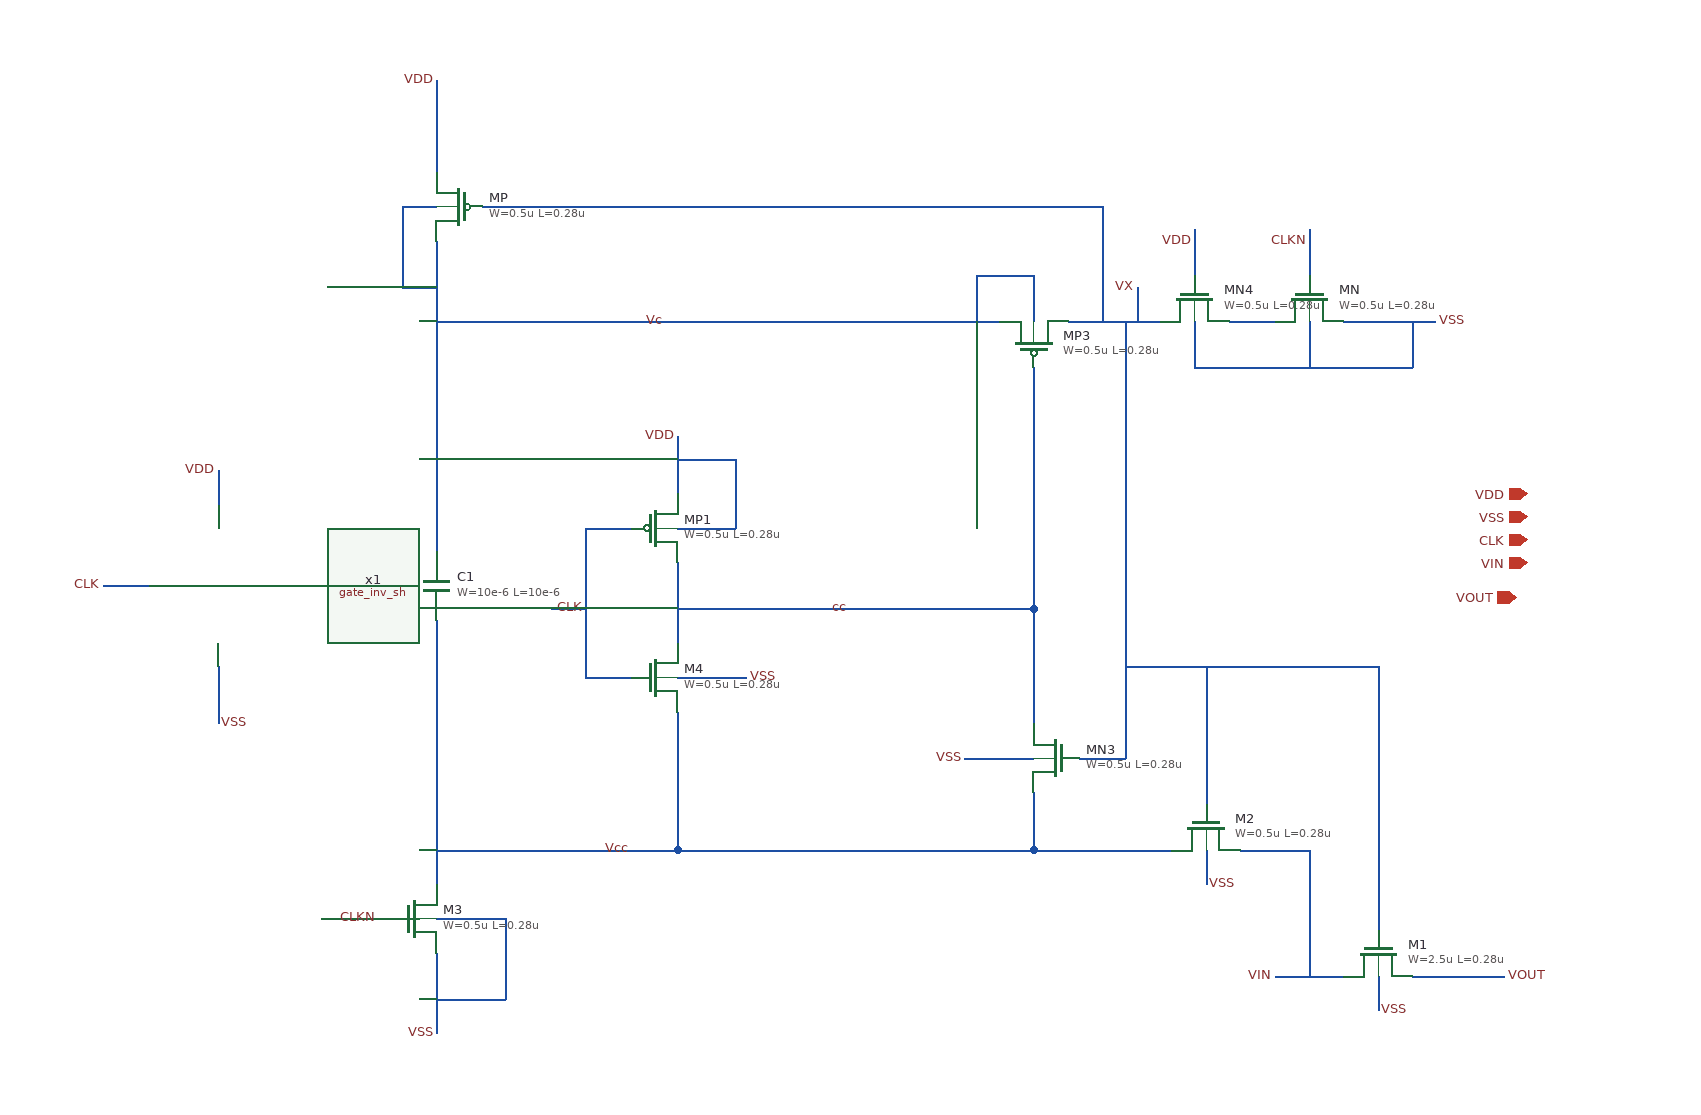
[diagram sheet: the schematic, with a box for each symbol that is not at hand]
v {xschem version=3.4.8RC file_version=1.3}
G {}
K {}
V {}
S {}
F {}
E {}
N 520 -490 520 -420 {lab=cc}
N 1000 -700 1040 -700 {lab=#net1}
N 1100 -700 1180 -700 {lab=VSS}
N 1070 -780 1070 -740 {lab=CLKN}
N 970 -780 970 -740 {lab=VDD}
N 860 -700 940 -700 {lab=VX}
N 1060 -130 1100 -130 {lab=VIN}
N 1130 -210 1130 -170 {lab=VX}
N 980 -320 980 -280 {lab=VX}
N 1130 -130 1130 -100 {lab=VSS}
N 980 -240 980 -210 {lab=VSS}
N 520 -450 830 -450 {lab=cc}
N 830 -360 830 -350 {lab=cc}
N 520 -360 520 -240 {lab=Vcc}
N 520 -240 830 -240 {lab=Vcc}
N 830 -290 830 -240 {lab=Vcc}
N 830 -450 830 -360 {lab=cc}
N 310 -150 310 -80 {lab=VSS}
N 310 -660 310 -500 {lab=Vc}
N 310 -440 310 -280 {lab=Vcc}
N 310 -280 310 -210 {lab=Vcc}
N 310 -770 310 -660 {lab=Vc}
N 310 -910 310 -830 {lab=VDD}
N 350 -800 890 -800 {lab=VX}
N 890 -800 890 -700 {lab=VX}
N 280 -800 310 -800 {lab=Vc}
N 280 -800 280 -730 {lab=Vc}
N 280 -730 310 -730 {lab=Vc}
N 310 -700 800 -700 {lab=Vc}
N 310 -180 370 -180 {lab=VSS}
N 370 -180 370 -110 {lab=VSS}
N 310 -110 370 -110 {lab=VSS}
N 210 -180 270 -180 {lab=CLKN}
N 440 -390 480 -390 {lab=CLK}
N 440 -520 480 -520 {lab=CLK}
N 440 -520 440 -390 {lab=CLK}
N 410 -450 440 -450 {lab=CLK}
N 470 -240 520 -240 {lab=Vcc}
N 310 -240 470 -240 {lab=Vcc}
N 520 -600 520 -550 {lab=VDD}
N 520 -390 580 -390 {lab=VSS}
N 520 -520 570 -520 {lab=VDD}
N 570 -580 570 -520 {lab=VDD}
N 520 -580 570 -580 {lab=VDD}
N 770 -320 830 -320 {lab=VSS}
N 830 -740 830 -700 {lab=Vc}
N 780 -740 830 -740 {lab=Vc}
N 780 -740 780 -700 {lab=Vc}
N 970 -700 970 -660 {lab=VSS}
N 970 -660 1160 -660 {lab=VSS}
N 1160 -700 1160 -660 {lab=VSS}
N 1070 -700 1070 -660 {lab=VSS}
N 910 -700 910 -320 {lab=VX}
N 910 -400 990 -400 {lab=VX}
N 990 -400 1090 -400 {lab=VX}
N 1160 -130 1240 -130 {lab=VOUT}
N 120 -400 120 -350 {lab=VSS}
N 120 -570 120 -540 {lab=VDD}
N 20 -470 60 -470 {lab=CLK}
N 200 -470 240 -470 {lab=CLKN}
N 890 -320 910 -320 {lab=VX}
N 870 -320 890 -320 {lab=VX}
N 830 -240 960 -240 {lab=Vcc}
N 1130 -400 1130 -210 {lab=VX}
N 1090 -400 1130 -400 {lab=VX}
N 1040 -130 1060 -130 {lab=VIN}
N 1010 -240 1070 -240 {lab=VIN}
N 1070 -240 1070 -130 {lab=VIN}
N 980 -400 980 -320 {lab=VX}
N 920 -730 920 -700 {lab=VX}
N 830 -470 830 -450 {lab=cc}
N 830 -660 830 -470 {lab=cc}
C {iopin.sym} 1260 -510 0 0 {name=p2 lab=CLK}
C {iopin.sym} 1260 -530 0 0 {name=p3 lab=VSS}
C {iopin.sym} 1260 -550 0 0 {name=p4 lab=VDD}
C {iopin.sym} 1250 -460 0 0 {name=p5 lab=VOUT}
C {iopin.sym} 1260 -490 0 0 {name=p6 lab=VIN}
C {lab_wire.sym} 310 -910 0 0 {name=p7 sig_type=std_logic lab=VDD}
C {lab_wire.sym} 970 -770 0 0 {name=p8 sig_type=std_logic lab=VDD}
C {lab_wire.sym} 1180 -700 0 1 {name=p10 sig_type=std_logic lab=VSS}
C {lab_wire.sym} 1240 -130 0 1 {name=p11 sig_type=std_logic lab=VOUT}
C {lab_wire.sym} 1040 -130 2 1 {name=p12 sig_type=std_logic lab=VIN}
C {lab_wire.sym} 980 -210 2 0 {name=p14 sig_type=std_logic lab=VSS}
C {lab_wire.sym} 770 -320 2 1 {name=p15 sig_type=std_logic lab=VSS}
C {lab_wire.sym} 310 -80 2 1 {name=p16 sig_type=std_logic lab=VSS}
C {lab_wire.sym} 580 -390 2 0 {name=p17 sig_type=std_logic lab=VSS}
C {lab_wire.sym} 520 -600 0 0 {name=p20 sig_type=std_logic lab=VDD}
C {lab_wire.sym} 120 -350 2 0 {name=p21 sig_type=std_logic lab=VSS}
C {lab_wire.sym} 20 -470 0 0 {name=p22 sig_type=std_logic lab=CLK}
C {lab_wire.sym} 120 -570 0 0 {name=p23 sig_type=std_logic lab=VDD}
C {lab_wire.sym} 1070 -770 0 0 {name=p26 sig_type=std_logic lab=CLKN
}
C {symbols/nfet_03v3.sym} 1070 -720 3 1 {name=MN
L=0.28u
W=0.5u
nf=1
m=2
ad="'int((nf+1)/2) * W/nf * 0.18u'"
pd="'2*int((nf+1)/2) * (W/nf + 0.18u)'"
as="'int((nf+2)/2) * W/nf * 0.18u'"
ps="'2*int((nf+2)/2) * (W/nf + 0.18u)'"
nrd="'0.18u / W'" nrs="'0.18u / W'"
sa=0 sb=0 sd=0
model=nfet_03v3
spiceprefix=X
}
C {symbols/nfet_03v3.sym} 850 -320 0 1 {name=MN3
L=0.28u
W=0.5u
nf=1
m=1
ad="'int((nf+1)/2) * W/nf * 0.18u'"
pd="'2*int((nf+1)/2) * (W/nf + 0.18u)'"
as="'int((nf+2)/2) * W/nf * 0.18u'"
ps="'2*int((nf+2)/2) * (W/nf + 0.18u)'"
nrd="'0.18u / W'" nrs="'0.18u / W'"
sa=0 sb=0 sd=0
model=nfet_03v3
spiceprefix=X
}
C {symbols/pfet_03v3.sym} 830 -680 3 0 {name=MP3
L=0.28u
W=0.5u
nf=1
m=2
ad="'int((nf+1)/2) * W/nf * 0.18u'"
pd="'2*int((nf+1)/2) * (W/nf + 0.18u)'"
as="'int((nf+2)/2) * W/nf * 0.18u'"
ps="'2*int((nf+2)/2) * (W/nf + 0.18u)'"
nrd="'0.18u / W'" nrs="'0.18u / W'"
sa=0 sb=0 sd=0
model=pfet_03v3
spiceprefix=X
}
C {symbols/nfet_03v3.sym} 970 -720 3 1 {name=MN4
L=0.28u
W=0.5u
nf=1
m=2
ad="'int((nf+1)/2) * W/nf * 0.18u'"
pd="'2*int((nf+1)/2) * (W/nf + 0.18u)'"
as="'int((nf+2)/2) * W/nf * 0.18u'"
ps="'2*int((nf+2)/2) * (W/nf + 0.18u)'"
nrd="'0.18u / W'" nrs="'0.18u / W'"
sa=0 sb=0 sd=0
model=nfet_03v3
spiceprefix=X
}
C {lab_wire.sym} 920 -730 0 0 {name=p1 sig_type=std_logic lab=VX}
C {lab_wire.sym} 670 -450 0 0 {name=p24 sig_type=std_logic lab=cc}
C {symbols/pfet_03v3.sym} 330 -800 0 1 {name=MP
L=0.28u
W=0.5u
nf=1
m=2
ad="'int((nf+1)/2) * W/nf * 0.18u'"
pd="'2*int((nf+1)/2) * (W/nf + 0.18u)'"
as="'int((nf+2)/2) * W/nf * 0.18u'"
ps="'2*int((nf+2)/2) * (W/nf + 0.18u)'"
nrd="'0.18u / W'" nrs="'0.18u / W'"
sa=0 sb=0 sd=0
model=pfet_03v3
spiceprefix=X
}
C {lab_wire.sym} 510 -700 0 0 {name=p25 sig_type=std_logic lab=Vc}
C {lab_wire.sym} 480 -240 0 0 {name=p27 sig_type=std_logic lab=Vcc}
C {lab_wire.sym} 1130 -100 2 0 {name=p13 sig_type=std_logic lab=VSS}
C {lab_wire.sym} 240 -470 0 1 {name=p9 sig_type=std_logic lab=CLKN
}
C {lab_wire.sym} 440 -450 0 0 {name=p19 sig_type=std_logic lab=CLK}
C {symbols/nfet_03v3.sym} 1130 -150 1 0 {name=M1
L=0.28u
W=2.5u
nf=1
m=1
ad="'int((nf+1)/2) * W/nf * 0.18u'"
pd="'2*int((nf+1)/2) * (W/nf + 0.18u)'"
as="'int((nf+2)/2) * W/nf * 0.18u'"
ps="'2*int((nf+2)/2) * (W/nf + 0.18u)'"
nrd="'0.18u / W'" nrs="'0.18u / W'"
sa=0 sb=0 sd=0
model=nfet_03v3
spiceprefix=X
}
C {symbols/nfet_03v3.sym} 980 -260 1 0 {name=M2
L=0.28u
W=0.5u
nf=1
m=1
ad="'int((nf+1)/2) * W/nf * 0.18u'"
pd="'2*int((nf+1)/2) * (W/nf + 0.18u)'"
as="'int((nf+2)/2) * W/nf * 0.18u'"
ps="'2*int((nf+2)/2) * (W/nf + 0.18u)'"
nrd="'0.18u / W'" nrs="'0.18u / W'"
sa=0 sb=0 sd=0
model=nfet_03v3
spiceprefix=X
}
C {symbols/nfet_03v3.sym} 290 -180 0 0 {name=M3
L=0.28u
W=0.5u
nf=1
m=1
ad="'int((nf+1)/2) * W/nf * 0.18u'"
pd="'2*int((nf+1)/2) * (W/nf + 0.18u)'"
as="'int((nf+2)/2) * W/nf * 0.18u'"
ps="'2*int((nf+2)/2) * (W/nf + 0.18u)'"
nrd="'0.18u / W'" nrs="'0.18u / W'"
sa=0 sb=0 sd=0
model=nfet_03v3
spiceprefix=X
}
C {symbols/nfet_03v3.sym} 500 -390 0 0 {name=M4
L=0.28u
W=0.5u
nf=1
m=1
ad="'int((nf+1)/2) * W/nf * 0.18u'"
pd="'2*int((nf+1)/2) * (W/nf + 0.18u)'"
as="'int((nf+2)/2) * W/nf * 0.18u'"
ps="'2*int((nf+2)/2) * (W/nf + 0.18u)'"
nrd="'0.18u / W'" nrs="'0.18u / W'"
sa=0 sb=0 sd=0
model=nfet_03v3
spiceprefix=X
}
C {designs/sar_adc/samplehold/gate_inv_sh/xschem/gate_inv_sh.sym} 120 -470 0 0 {name=x1}
C {lab_wire.sym} 260 -180 0 0 {name=p28 sig_type=std_logic lab=CLKN
}
C {symbols/pfet_03v3.sym} 500 -520 0 0 {name=MP1
L=0.28u
W=0.5u
nf=1
m=2
ad="'int((nf+1)/2) * W/nf * 0.18u'"
pd="'2*int((nf+1)/2) * (W/nf + 0.18u)'"
as="'int((nf+2)/2) * W/nf * 0.18u'"
ps="'2*int((nf+2)/2) * (W/nf + 0.18u)'"
nrd="'0.18u / W'" nrs="'0.18u / W'"
sa=0 sb=0 sd=0
model=pfet_03v3
spiceprefix=X
}
C {symbols/cap_mim_2f0fF.sym} 310 -470 0 0 {name=C1
W=10e-6
L=10e-6
model=cap_mim_2f0fF
spiceprefix=X
m=1}
